One B-rep face of a CAD part: STEP entity #150774.
In plain terms, the planar face has unit normal (0, 0.707, 0.707).
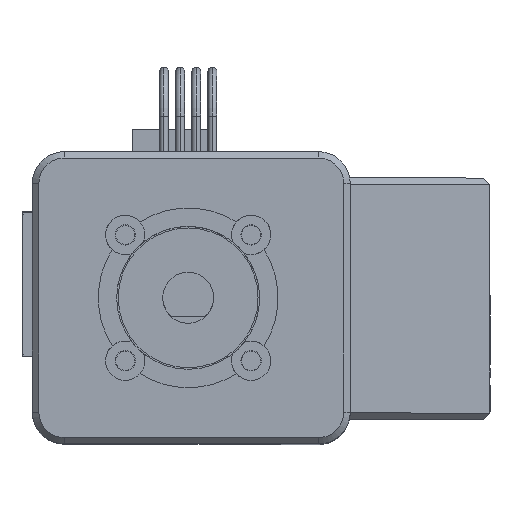
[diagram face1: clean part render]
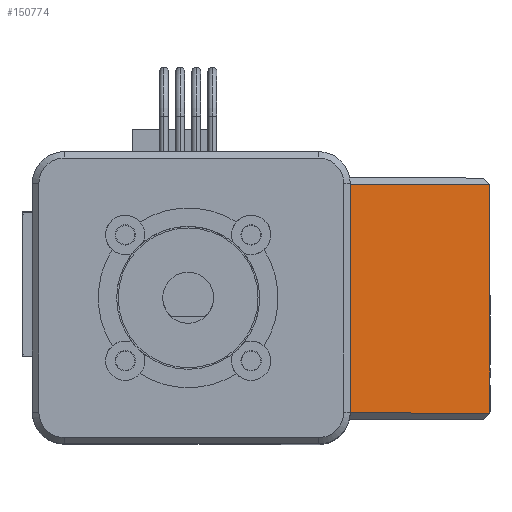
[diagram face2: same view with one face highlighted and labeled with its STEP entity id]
Its self-contained STEP definition (entity closure, numbers rounded to 3 decimals):
#143965 = PLANE('',#143966);
#143966 = AXIS2_PLACEMENT_3D('',#143967,#143968,#143969);
#143967 = CARTESIAN_POINT('',(0.,6.,0.));
#143968 = DIRECTION('',(0.,1.,0.));
#143969 = DIRECTION('',(0.,-0.,1.));
#148290 = PLANE('',#148291);
#148291 = AXIS2_PLACEMENT_3D('',#148292,#148293,#148294);
#148292 = CARTESIAN_POINT('',(19.,-4.95,40.536));
#148293 = DIRECTION('',(-0.707,-0.5,-0.5));
#148294 = DIRECTION('',(0.,-0.707,0.707));
#148461 = PLANE('',#148462);
#148462 = AXIS2_PLACEMENT_3D('',#148463,#148464,#148465);
#148463 = CARTESIAN_POINT('',(-18.,6.,31.));
#148464 = DIRECTION('',(0.707,-0.5,-0.5));
#148465 = DIRECTION('',(0.,-0.707,0.707));
#149789 = VERTEX_POINT('',#149790);
#149790 = CARTESIAN_POINT('',(-18.,6.,31.));
#149811 = EDGE_CURVE('',#149789,#149812,#149814,.T.);
#149812 = VERTEX_POINT('',#149813);
#149813 = CARTESIAN_POINT('',(18.,6.,31.));
#149814 = SURFACE_CURVE('',#149815,(#149819,#149826),.PCURVE_S1.);
#149815 = LINE('',#149816,#149817);
#149816 = CARTESIAN_POINT('',(-19.,6.,31.));
#149817 = VECTOR('',#149818,1.);
#149818 = DIRECTION('',(1.,0.,0.));
#149819 = PCURVE('',#143965,#149820);
#149820 = DEFINITIONAL_REPRESENTATION('',(#149821),#149825);
#149821 = LINE('',#149822,#149823);
#149822 = CARTESIAN_POINT('',(31.,-19.));
#149823 = VECTOR('',#149824,1.);
#149824 = DIRECTION('',(0.,1.));
#149825 = ( GEOMETRIC_REPRESENTATION_CONTEXT(2) 
PARAMETRIC_REPRESENTATION_CONTEXT() REPRESENTATION_CONTEXT('2D SPACE',''
  ) );
#149826 = PCURVE('',#149827,#149832);
#149827 = PLANE('',#149828);
#149828 = AXIS2_PLACEMENT_3D('',#149829,#149830,#149831);
#149829 = CARTESIAN_POINT('',(-50.113,6.,31.));
#149830 = DIRECTION('',(-0.,0.707,0.707));
#149831 = DIRECTION('',(0.,-0.707,0.707));
#149832 = DEFINITIONAL_REPRESENTATION('',(#149833),#149837);
#149833 = LINE('',#149834,#149835);
#149834 = CARTESIAN_POINT('',(0.,31.113));
#149835 = VECTOR('',#149836,1.);
#149836 = DIRECTION('',(0.,1.));
#149837 = ( GEOMETRIC_REPRESENTATION_CONTEXT(2) 
PARAMETRIC_REPRESENTATION_CONTEXT() REPRESENTATION_CONTEXT('2D SPACE',''
  ) );
#149875 = PLANE('',#149876);
#149876 = AXIS2_PLACEMENT_3D('',#149877,#149878,#149879);
#149877 = CARTESIAN_POINT('',(-19.,-16.,116.));
#149878 = DIRECTION('',(0.,-1.,0.));
#149879 = DIRECTION('',(0.,-0.,-1.));
#149923 = VERTEX_POINT('',#149924);
#149924 = CARTESIAN_POINT('',(18.,-16.,53.));
#149945 = EDGE_CURVE('',#149946,#149923,#149948,.T.);
#149946 = VERTEX_POINT('',#149947);
#149947 = CARTESIAN_POINT('',(-18.,-16.,53.));
#149948 = SURFACE_CURVE('',#149949,(#149953,#149960),.PCURVE_S1.);
#149949 = LINE('',#149950,#149951);
#149950 = CARTESIAN_POINT('',(-50.113,-16.,53.));
#149951 = VECTOR('',#149952,1.);
#149952 = DIRECTION('',(1.,0.,0.));
#149953 = PCURVE('',#149875,#149954);
#149954 = DEFINITIONAL_REPRESENTATION('',(#149955),#149959);
#149955 = LINE('',#149956,#149957);
#149956 = CARTESIAN_POINT('',(63.,-31.113));
#149957 = VECTOR('',#149958,1.);
#149958 = DIRECTION('',(0.,1.));
#149959 = ( GEOMETRIC_REPRESENTATION_CONTEXT(2) 
PARAMETRIC_REPRESENTATION_CONTEXT() REPRESENTATION_CONTEXT('2D SPACE',''
  ) );
#149960 = PCURVE('',#149827,#149961);
#149961 = DEFINITIONAL_REPRESENTATION('',(#149962),#149966);
#149962 = LINE('',#149963,#149964);
#149963 = CARTESIAN_POINT('',(31.113,0.));
#149964 = VECTOR('',#149965,1.);
#149965 = DIRECTION('',(0.,1.));
#149966 = ( GEOMETRIC_REPRESENTATION_CONTEXT(2) 
PARAMETRIC_REPRESENTATION_CONTEXT() REPRESENTATION_CONTEXT('2D SPACE',''
  ) );
#150774 = ADVANCED_FACE('',(#150775),#149827,.T.);
#150775 = FACE_BOUND('',#150776,.T.);
#150776 = EDGE_LOOP('',(#150777,#150778,#150799,#150800));
#150777 = ORIENTED_EDGE('',*,*,#149811,.F.);
#150778 = ORIENTED_EDGE('',*,*,#150779,.T.);
#150779 = EDGE_CURVE('',#149789,#149946,#150780,.T.);
#150780 = SURFACE_CURVE('',#150781,(#150785,#150792),.PCURVE_S1.);
#150781 = LINE('',#150782,#150783);
#150782 = CARTESIAN_POINT('',(-18.,6.,31.));
#150783 = VECTOR('',#150784,1.);
#150784 = DIRECTION('',(0.,-0.707,0.707));
#150785 = PCURVE('',#149827,#150786);
#150786 = DEFINITIONAL_REPRESENTATION('',(#150787),#150791);
#150787 = LINE('',#150788,#150789);
#150788 = CARTESIAN_POINT('',(0.,32.113));
#150789 = VECTOR('',#150790,1.);
#150790 = DIRECTION('',(1.,0.));
#150791 = ( GEOMETRIC_REPRESENTATION_CONTEXT(2) 
PARAMETRIC_REPRESENTATION_CONTEXT() REPRESENTATION_CONTEXT('2D SPACE',''
  ) );
#150792 = PCURVE('',#148461,#150793);
#150793 = DEFINITIONAL_REPRESENTATION('',(#150794),#150798);
#150794 = LINE('',#150795,#150796);
#150795 = CARTESIAN_POINT('',(0.,-0.));
#150796 = VECTOR('',#150797,1.);
#150797 = DIRECTION('',(1.,0.));
#150798 = ( GEOMETRIC_REPRESENTATION_CONTEXT(2) 
PARAMETRIC_REPRESENTATION_CONTEXT() REPRESENTATION_CONTEXT('2D SPACE',''
  ) );
#150799 = ORIENTED_EDGE('',*,*,#149945,.T.);
#150800 = ORIENTED_EDGE('',*,*,#150801,.T.);
#150801 = EDGE_CURVE('',#149923,#149812,#150802,.T.);
#150802 = SURFACE_CURVE('',#150803,(#150807,#150814),.PCURVE_S1.);
#150803 = LINE('',#150804,#150805);
#150804 = CARTESIAN_POINT('',(18.,6.,31.));
#150805 = VECTOR('',#150806,1.);
#150806 = DIRECTION('',(0.,0.707,-0.707));
#150807 = PCURVE('',#149827,#150808);
#150808 = DEFINITIONAL_REPRESENTATION('',(#150809),#150813);
#150809 = LINE('',#150810,#150811);
#150810 = CARTESIAN_POINT('',(0.,68.113));
#150811 = VECTOR('',#150812,1.);
#150812 = DIRECTION('',(-1.,0.));
#150813 = ( GEOMETRIC_REPRESENTATION_CONTEXT(2) 
PARAMETRIC_REPRESENTATION_CONTEXT() REPRESENTATION_CONTEXT('2D SPACE',''
  ) );
#150814 = PCURVE('',#148290,#150815);
#150815 = DEFINITIONAL_REPRESENTATION('',(#150816),#150820);
#150816 = LINE('',#150817,#150818);
#150817 = CARTESIAN_POINT('',(-14.486,1.414));
#150818 = VECTOR('',#150819,1.);
#150819 = DIRECTION('',(-1.,0.));
#150820 = ( GEOMETRIC_REPRESENTATION_CONTEXT(2) 
PARAMETRIC_REPRESENTATION_CONTEXT() REPRESENTATION_CONTEXT('2D SPACE',''
  ) );
